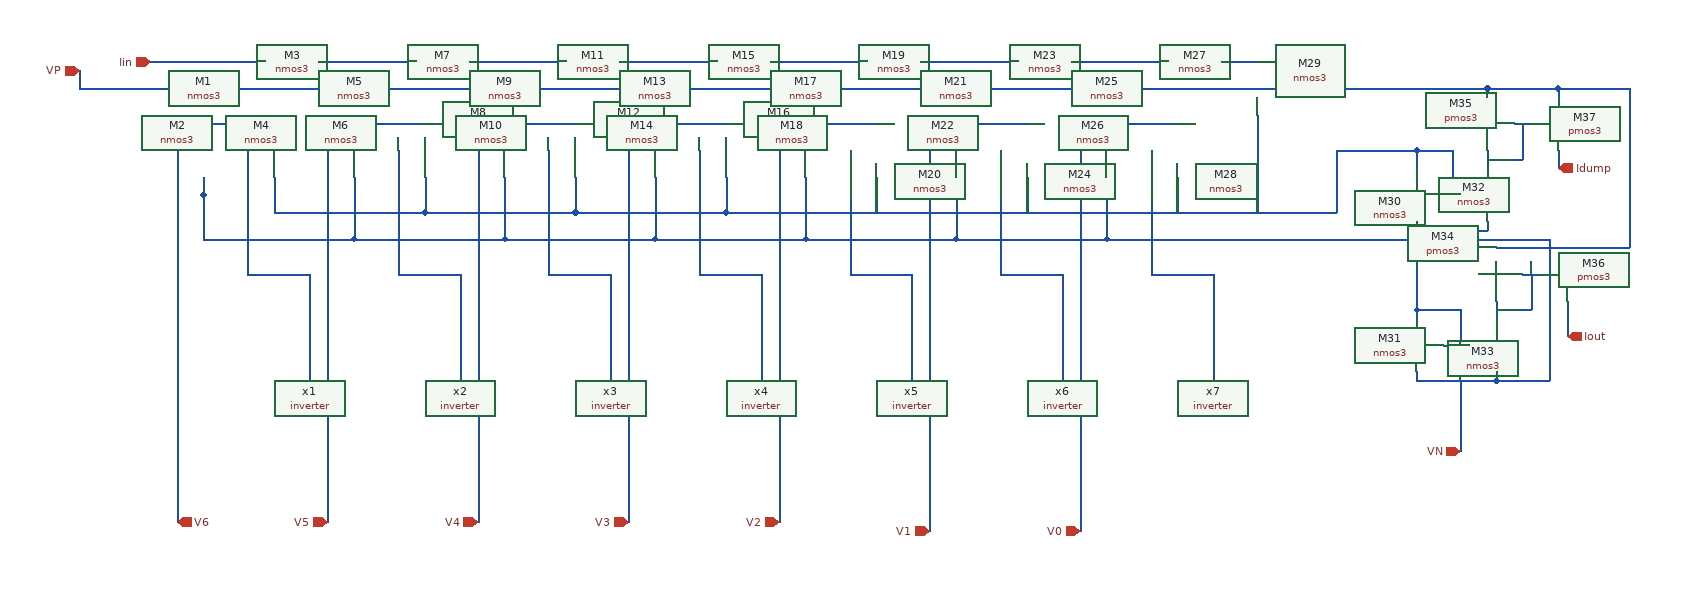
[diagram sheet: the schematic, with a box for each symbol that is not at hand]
v {xschem version=3.4.3 file_version=1.2
}
G {}
K {}
V {}
S {}
E {}
N 240 -30 310 -30 {
lab=VP}
N 240 30 240 40 {
lab=#net1}
N 240 100 240 120 {
lab=VP}
N 410 -30 480 -30 {
lab=VP}
N 410 30 410 40 {
lab=#net2}
N 370 -30 410 -30 {
lab=VP}
N 240 40 320 40 {
lab=#net1}
N 410 30 410 40 {
lab=#net2}
N 410 100 410 120 {
lab=VP}
N 490 100 490 120 {
lab=VP}
N 410 40 490 40 {
lab=#net2}
N 240 30 240 40 {
lab=#net1}
N 240 100 240 120 {
lab=VP}
N 320 100 320 120 {
lab=VP}
N 240 40 320 40 {
lab=#net1}
N 580 -30 650 -30 {
lab=VP}
N 580 30 580 40 {
lab=#net3}
N 540 -30 580 -30 {
lab=VP}
N 580 30 580 40 {
lab=#net3}
N 580 100 580 120 {
lab=VP}
N 660 100 660 120 {
lab=VP}
N 580 40 660 40 {
lab=#net3}
N 750 -30 820 -30 {
lab=VP}
N 750 30 750 40 {
lab=#net4}
N 710 -30 750 -30 {
lab=VP}
N 750 30 750 40 {
lab=#net4}
N 750 100 750 120 {
lab=VP}
N 830 100 830 120 {
lab=VP}
N 750 40 830 40 {
lab=#net4}
N 920 -30 990 -30 {
lab=VP}
N 920 30 920 40 {
lab=#net5}
N 880 -30 920 -30 {
lab=VP}
N 920 30 920 40 {
lab=#net5}
N 920 100 920 120 {
lab=VP}
N 1000 100 1000 120 {
lab=VP}
N 920 40 1000 40 {
lab=#net5}
N 1090 -30 1160 -30 {
lab=VP}
N 1090 30 1090 40 {
lab=#net6}
N 1050 -30 1090 -30 {
lab=VP}
N 1090 30 1090 40 {
lab=#net6}
N 1090 100 1090 120 {
lab=VP}
N 1170 100 1170 120 {
lab=VP}
N 1090 40 1170 40 {
lab=#net6}
N 1260 -30 1330 -30 {
lab=VP}
N 1260 30 1260 40 {
lab=#net7}
N 1220 -30 1260 -30 {
lab=VP}
N 1260 30 1260 40 {
lab=#net7}
N 1260 100 1260 120 {
lab=VP}
N 1340 100 1340 120 {
lab=VP}
N 1260 40 1340 40 {
lab=#net7}
N 1390 -30 1430 -30 {
lab=VP}
N 240 120 240 170 {
lab=VP}
N 240 170 410 170 {
lab=VP}
N 410 120 410 170 {
lab=VP}
N 410 170 580 170 {
lab=VP}
N 580 120 580 170 {
lab=VP}
N 750 120 750 170 {
lab=VP}
N 580 170 750 170 {
lab=VP}
N 920 120 920 170 {
lab=VP}
N 750 170 920 170 {
lab=VP}
N 1090 120 1090 170 {
lab=VP}
N 920 170 1090 170 {
lab=VP}
N 1260 120 1260 170 {
lab=VP}
N 1090 170 1260 170 {
lab=VP}
N 320 120 320 140 {
lab=VP}
N 320 140 490 140 {
lab=VP}
N 490 120 490 140 {
lab=VP}
N 490 140 660 140 {
lab=VP}
N 660 120 660 140 {
lab=VP}
N 660 140 830 140 {
lab=VP}
N 830 120 830 140 {
lab=VP}
N 1000 120 1000 140 {
lab=VP}
N 830 140 1450 140 {
lab=VP}
N 1170 120 1170 140 {
lab=VP}
N 1340 120 1340 140 {
lab=VP}
N 1430 30 1430 140 {
lab=VP}
N 180 -30 240 -30 {
lab=VP}
N 210 0 340 0 {
lab=VP}
N 340 0 380 0 {
lab=VP}
N 380 0 510 0 {
lab=VP}
N 510 0 550 -0 {
lab=VP}
N 550 -0 680 0 {
lab=VP}
N 680 0 720 0 {
lab=VP}
N 190 0 210 -0 {
lab=VP}
N 210 70 210 320 {
lab=V6}
N 380 70 380 320 {
lab=V5}
N 550 70 550 310 {
lab=V4}
N 550 310 550 320 {
lab=V4}
N 720 70 720 320 {
lab=V3}
N 890 70 890 320 {
lab=V2}
N 1060 70 1060 320 {
lab=V1}
N 1230 70 1230 320 {
lab=V0}
N 180 0 190 0 {
lab=VP}
N 720 -0 1400 0 {
lab=VP}
N 210 320 210 490 {
lab=V6}
N 380 320 380 490 {
lab=V5}
N 550 320 550 490 {
lab=V4}
N 720 320 720 490 {
lab=V3}
N 890 320 890 480 {
lab=V2}
N 1060 320 1060 480 {
lab=V1}
N 1230 320 1230 480 {
lab=V0}
N 1260 170 1450 170 {
lab=VP}
N 890 480 890 490 {
lab=V2}
N 1060 480 1060 500 {
lab=V1}
N 1230 480 1230 500 {
lab=V0}
N 290 70 290 210 {
lab=#net8}
N 290 210 360 210 {
lab=#net8}
N 360 210 360 330 {
lab=#net8}
N 460 70 460 200 {
lab=#net9}
N 460 200 460 210 {
lab=#net9}
N 460 210 530 210 {
lab=#net9}
N 530 210 530 330 {
lab=#net9}
N 630 70 630 210 {
lab=#net10}
N 630 210 700 210 {
lab=#net10}
N 700 210 700 330 {
lab=#net10}
N 800 70 800 210 {
lab=#net11}
N 800 210 870 210 {
lab=#net11}
N 870 210 870 330 {
lab=#net11}
N 970 70 970 210 {
lab=#net12}
N 970 210 1040 210 {
lab=#net12}
N 1040 210 1040 330 {
lab=#net12}
N 1140 70 1140 210 {
lab=#net13}
N 1140 210 1200 210 {
lab=#net13}
N 1200 210 1210 210 {
lab=#net13}
N 1210 210 1210 330 {
lab=#net13}
N 1310 70 1310 210 {
lab=#net14}
N 1310 210 1380 210 {
lab=#net14}
N 1380 210 1380 330 {
lab=#net14}
N 1450 140 1520 140 {
lab=VP}
N 1450 170 1510 170 {
lab=VP}
N 100 -20 100 0 {
lab=VP}
N 100 0 180 0 {
lab=VP}
N 1640 290 1670 290 {
lab=VP}
N 1640 120 1660 120 {
lab=VP}
N 1610 150 1610 160 {
lab=VN}
N 1610 160 1690 160 {
lab=VN}
N 1650 160 1650 170 {
lab=VN}
N 1610 320 1610 330 {
lab=VN}
N 1610 330 1700 330 {
lab=VN}
N 1700 320 1700 330 {
lab=VN}
N 1690 70 1690 90 {
lab=#net15}
N 1660 250 1660 290 {
lab=VP}
N 1610 70 1610 90 {
lab=VP}
N 1610 250 1610 260 {
lab=VP}
N 1770 70 1770 90 {
lab=Idump}
N 1720 40 1740 40 {
lab=#net15}
N 1730 40 1730 80 {
lab=#net15}
N 1610 70 1650 70 {
lab=VP}
N 1650 70 1650 120 {
lab=VP}
N 1690 80 1730 80 {
lab=#net15}
N 1610 250 1660 250 {
lab=VP}
N 1690 150 1690 160 {
lab=VN}
N 1700 240 1700 260 {
lab=#net16}
N 1780 240 1780 260 {
lab=Iout}
N 1730 210 1750 210 {
lab=#net16}
N 1740 210 1740 250 {
lab=#net16}
N 1700 250 1740 250 {
lab=#net16}
N 1510 170 1610 170 {
lab=VP}
N 1610 170 1610 250 {
lab=VP}
N 1520 70 1520 140 {
lab=VP}
N 1520 70 1610 70 {
lab=VP}
N 1400 0 1690 0 {
lab=VP}
N 1690 0 1690 10 {
lab=VP}
N 1690 -0 1770 0 {
lab=VP}
N 1770 0 1770 10 {
lab=VP}
N 1770 0 1850 0 {
lab=VP}
N 1850 0 1850 180 {
lab=VP}
N 1780 180 1850 180 {
lab=VP}
N 1700 180 1780 180 {
lab=VP}
N 1780 260 1780 280 {
lab=Iout}
N 1650 170 1760 170 {
lab=VN}
N 1760 170 1760 330 {
lab=VN}
N 1700 330 1760 330 {
lab=VN}
N 1660 330 1660 410 {
lab=VN}
C {madvlsi/nmos3.sym} 240 0 0 0 {name=M1
L=4
W=12
body=GND
nf=1
mult=1
ad="'int((nf+1)/2) * W/nf * 0.29'" 
pd="'2*int((nf+1)/2) * (W/nf + 0.29)'"
as="'int((nf+2)/2) * W/nf * 0.29'" 
ps="'2*int((nf+2)/2) * (W/nf + 0.29)'"
nrd="'0.29 / W'" nrs="'0.29 / W'"
sa=0 sb=0 sd=0
model=nfet_01v8
spiceprefix=X
}
C {madvlsi/nmos3.sym} 340 -30 3 0 {name=M3
L=4
W=12
body=GND
nf=1
mult=1
ad="'int((nf+1)/2) * W/nf * 0.29'" 
pd="'2*int((nf+1)/2) * (W/nf + 0.29)'"
as="'int((nf+2)/2) * W/nf * 0.29'" 
ps="'2*int((nf+2)/2) * (W/nf + 0.29)'"
nrd="'0.29 / W'" nrs="'0.29 / W'"
sa=0 sb=0 sd=0
model=nfet_01v8
spiceprefix=X
}
C {madvlsi/nmos3.sym} 410 0 0 0 {name=M5
L=4
W=12
body=GND
nf=1
mult=1
ad="'int((nf+1)/2) * W/nf * 0.29'" 
pd="'2*int((nf+1)/2) * (W/nf + 0.29)'"
as="'int((nf+2)/2) * W/nf * 0.29'" 
ps="'2*int((nf+2)/2) * (W/nf + 0.29)'"
nrd="'0.29 / W'" nrs="'0.29 / W'"
sa=0 sb=0 sd=0
model=nfet_01v8
spiceprefix=X
}
C {madvlsi/nmos3.sym} 510 -30 3 0 {name=M7
L=4
W=12
body=GND
nf=1
mult=1
ad="'int((nf+1)/2) * W/nf * 0.29'" 
pd="'2*int((nf+1)/2) * (W/nf + 0.29)'"
as="'int((nf+2)/2) * W/nf * 0.29'" 
ps="'2*int((nf+2)/2) * (W/nf + 0.29)'"
nrd="'0.29 / W'" nrs="'0.29 / W'"
sa=0 sb=0 sd=0
model=nfet_01v8
spiceprefix=X
}
C {madvlsi/nmos3.sym} 410 70 0 0 {name=M6
L=4
W=12
body=GND
nf=1
mult=1
ad="'int((nf+1)/2) * W/nf * 0.29'" 
pd="'2*int((nf+1)/2) * (W/nf + 0.29)'"
as="'int((nf+2)/2) * W/nf * 0.29'" 
ps="'2*int((nf+2)/2) * (W/nf + 0.29)'"
nrd="'0.29 / W'" nrs="'0.29 / W'"
sa=0 sb=0 sd=0
model=nfet_01v8
spiceprefix=X
}
C {madvlsi/nmos3.sym} 490 70 0 0 {name=M8
L=4
W=12
body=GND
nf=1
mult=1
ad="'int((nf+1)/2) * W/nf * 0.29'" 
pd="'2*int((nf+1)/2) * (W/nf + 0.29)'"
as="'int((nf+2)/2) * W/nf * 0.29'" 
ps="'2*int((nf+2)/2) * (W/nf + 0.29)'"
nrd="'0.29 / W'" nrs="'0.29 / W'"
sa=0 sb=0 sd=0
model=nfet_01v8
spiceprefix=X
}
C {madvlsi/nmos3.sym} 240 70 0 0 {name=M2
L=4
W=12
body=GND
nf=1
mult=1
ad="'int((nf+1)/2) * W/nf * 0.29'" 
pd="'2*int((nf+1)/2) * (W/nf + 0.29)'"
as="'int((nf+2)/2) * W/nf * 0.29'" 
ps="'2*int((nf+2)/2) * (W/nf + 0.29)'"
nrd="'0.29 / W'" nrs="'0.29 / W'"
sa=0 sb=0 sd=0
model=nfet_01v8
spiceprefix=X
}
C {madvlsi/nmos3.sym} 320 70 0 0 {name=M4
L=4
W=12
body=GND
nf=1
mult=1
ad="'int((nf+1)/2) * W/nf * 0.29'" 
pd="'2*int((nf+1)/2) * (W/nf + 0.29)'"
as="'int((nf+2)/2) * W/nf * 0.29'" 
ps="'2*int((nf+2)/2) * (W/nf + 0.29)'"
nrd="'0.29 / W'" nrs="'0.29 / W'"
sa=0 sb=0 sd=0
model=nfet_01v8
spiceprefix=X
}
C {madvlsi/nmos3.sym} 580 0 0 0 {name=M9
L=4
W=12
body=GND
nf=1
mult=1
ad="'int((nf+1)/2) * W/nf * 0.29'" 
pd="'2*int((nf+1)/2) * (W/nf + 0.29)'"
as="'int((nf+2)/2) * W/nf * 0.29'" 
ps="'2*int((nf+2)/2) * (W/nf + 0.29)'"
nrd="'0.29 / W'" nrs="'0.29 / W'"
sa=0 sb=0 sd=0
model=nfet_01v8
spiceprefix=X
}
C {madvlsi/nmos3.sym} 680 -30 3 0 {name=M11
L=4
W=12
body=GND
nf=1
mult=1
ad="'int((nf+1)/2) * W/nf * 0.29'" 
pd="'2*int((nf+1)/2) * (W/nf + 0.29)'"
as="'int((nf+2)/2) * W/nf * 0.29'" 
ps="'2*int((nf+2)/2) * (W/nf + 0.29)'"
nrd="'0.29 / W'" nrs="'0.29 / W'"
sa=0 sb=0 sd=0
model=nfet_01v8
spiceprefix=X
}
C {madvlsi/nmos3.sym} 580 70 0 0 {name=M10
L=4
W=12
body=GND
nf=1
mult=1
ad="'int((nf+1)/2) * W/nf * 0.29'" 
pd="'2*int((nf+1)/2) * (W/nf + 0.29)'"
as="'int((nf+2)/2) * W/nf * 0.29'" 
ps="'2*int((nf+2)/2) * (W/nf + 0.29)'"
nrd="'0.29 / W'" nrs="'0.29 / W'"
sa=0 sb=0 sd=0
model=nfet_01v8
spiceprefix=X
}
C {madvlsi/nmos3.sym} 660 70 0 0 {name=M12
L=4
W=12
body=GND
nf=1
mult=1
ad="'int((nf+1)/2) * W/nf * 0.29'" 
pd="'2*int((nf+1)/2) * (W/nf + 0.29)'"
as="'int((nf+2)/2) * W/nf * 0.29'" 
ps="'2*int((nf+2)/2) * (W/nf + 0.29)'"
nrd="'0.29 / W'" nrs="'0.29 / W'"
sa=0 sb=0 sd=0
model=nfet_01v8
spiceprefix=X
}
C {madvlsi/nmos3.sym} 750 0 0 0 {name=M13
L=4
W=12
body=GND
nf=1
mult=1
ad="'int((nf+1)/2) * W/nf * 0.29'" 
pd="'2*int((nf+1)/2) * (W/nf + 0.29)'"
as="'int((nf+2)/2) * W/nf * 0.29'" 
ps="'2*int((nf+2)/2) * (W/nf + 0.29)'"
nrd="'0.29 / W'" nrs="'0.29 / W'"
sa=0 sb=0 sd=0
model=nfet_01v8
spiceprefix=X
}
C {madvlsi/nmos3.sym} 850 -30 3 0 {name=M15
L=4
W=12
body=GND
nf=1
mult=1
ad="'int((nf+1)/2) * W/nf * 0.29'" 
pd="'2*int((nf+1)/2) * (W/nf + 0.29)'"
as="'int((nf+2)/2) * W/nf * 0.29'" 
ps="'2*int((nf+2)/2) * (W/nf + 0.29)'"
nrd="'0.29 / W'" nrs="'0.29 / W'"
sa=0 sb=0 sd=0
model=nfet_01v8
spiceprefix=X
}
C {madvlsi/nmos3.sym} 750 70 0 0 {name=M14
L=4
W=12
body=GND
nf=1
mult=1
ad="'int((nf+1)/2) * W/nf * 0.29'" 
pd="'2*int((nf+1)/2) * (W/nf + 0.29)'"
as="'int((nf+2)/2) * W/nf * 0.29'" 
ps="'2*int((nf+2)/2) * (W/nf + 0.29)'"
nrd="'0.29 / W'" nrs="'0.29 / W'"
sa=0 sb=0 sd=0
model=nfet_01v8
spiceprefix=X
}
C {madvlsi/nmos3.sym} 830 70 0 0 {name=M16
L=4
W=12
body=GND
nf=1
mult=1
ad="'int((nf+1)/2) * W/nf * 0.29'" 
pd="'2*int((nf+1)/2) * (W/nf + 0.29)'"
as="'int((nf+2)/2) * W/nf * 0.29'" 
ps="'2*int((nf+2)/2) * (W/nf + 0.29)'"
nrd="'0.29 / W'" nrs="'0.29 / W'"
sa=0 sb=0 sd=0
model=nfet_01v8
spiceprefix=X
}
C {madvlsi/nmos3.sym} 920 0 0 0 {name=M17
L=4
W=12
body=GND
nf=1
mult=1
ad="'int((nf+1)/2) * W/nf * 0.29'" 
pd="'2*int((nf+1)/2) * (W/nf + 0.29)'"
as="'int((nf+2)/2) * W/nf * 0.29'" 
ps="'2*int((nf+2)/2) * (W/nf + 0.29)'"
nrd="'0.29 / W'" nrs="'0.29 / W'"
sa=0 sb=0 sd=0
model=nfet_01v8
spiceprefix=X
}
C {madvlsi/nmos3.sym} 1020 -30 3 0 {name=M19
L=4
W=12
body=GND
nf=1
mult=1
ad="'int((nf+1)/2) * W/nf * 0.29'" 
pd="'2*int((nf+1)/2) * (W/nf + 0.29)'"
as="'int((nf+2)/2) * W/nf * 0.29'" 
ps="'2*int((nf+2)/2) * (W/nf + 0.29)'"
nrd="'0.29 / W'" nrs="'0.29 / W'"
sa=0 sb=0 sd=0
model=nfet_01v8
spiceprefix=X
}
C {madvlsi/nmos3.sym} 920 70 0 0 {name=M18
L=4
W=12
body=GND
nf=1
mult=1
ad="'int((nf+1)/2) * W/nf * 0.29'" 
pd="'2*int((nf+1)/2) * (W/nf + 0.29)'"
as="'int((nf+2)/2) * W/nf * 0.29'" 
ps="'2*int((nf+2)/2) * (W/nf + 0.29)'"
nrd="'0.29 / W'" nrs="'0.29 / W'"
sa=0 sb=0 sd=0
model=nfet_01v8
spiceprefix=X
}
C {madvlsi/nmos3.sym} 1000 70 0 0 {name=M20
L=4
W=12
body=GND
nf=1
mult=1
ad="'int((nf+1)/2) * W/nf * 0.29'" 
pd="'2*int((nf+1)/2) * (W/nf + 0.29)'"
as="'int((nf+2)/2) * W/nf * 0.29'" 
ps="'2*int((nf+2)/2) * (W/nf + 0.29)'"
nrd="'0.29 / W'" nrs="'0.29 / W'"
sa=0 sb=0 sd=0
model=nfet_01v8
spiceprefix=X
}
C {madvlsi/nmos3.sym} 1090 0 0 0 {name=M21
L=4
W=12
body=GND
nf=1
mult=1
ad="'int((nf+1)/2) * W/nf * 0.29'" 
pd="'2*int((nf+1)/2) * (W/nf + 0.29)'"
as="'int((nf+2)/2) * W/nf * 0.29'" 
ps="'2*int((nf+2)/2) * (W/nf + 0.29)'"
nrd="'0.29 / W'" nrs="'0.29 / W'"
sa=0 sb=0 sd=0
model=nfet_01v8
spiceprefix=X
}
C {madvlsi/nmos3.sym} 1190 -30 3 0 {name=M23
L=4
W=12
body=GND
nf=1
mult=1
ad="'int((nf+1)/2) * W/nf * 0.29'" 
pd="'2*int((nf+1)/2) * (W/nf + 0.29)'"
as="'int((nf+2)/2) * W/nf * 0.29'" 
ps="'2*int((nf+2)/2) * (W/nf + 0.29)'"
nrd="'0.29 / W'" nrs="'0.29 / W'"
sa=0 sb=0 sd=0
model=nfet_01v8
spiceprefix=X
}
C {madvlsi/nmos3.sym} 1090 70 0 0 {name=M22
L=4
W=12
body=GND
nf=1
mult=1
ad="'int((nf+1)/2) * W/nf * 0.29'" 
pd="'2*int((nf+1)/2) * (W/nf + 0.29)'"
as="'int((nf+2)/2) * W/nf * 0.29'" 
ps="'2*int((nf+2)/2) * (W/nf + 0.29)'"
nrd="'0.29 / W'" nrs="'0.29 / W'"
sa=0 sb=0 sd=0
model=nfet_01v8
spiceprefix=X
}
C {madvlsi/nmos3.sym} 1170 70 0 0 {name=M24
L=4
W=12
body=GND
nf=1
mult=1
ad="'int((nf+1)/2) * W/nf * 0.29'" 
pd="'2*int((nf+1)/2) * (W/nf + 0.29)'"
as="'int((nf+2)/2) * W/nf * 0.29'" 
ps="'2*int((nf+2)/2) * (W/nf + 0.29)'"
nrd="'0.29 / W'" nrs="'0.29 / W'"
sa=0 sb=0 sd=0
model=nfet_01v8
spiceprefix=X
}
C {madvlsi/nmos3.sym} 1260 0 0 0 {name=M25
L=4
W=12
body=GND
nf=1
mult=1
ad="'int((nf+1)/2) * W/nf * 0.29'" 
pd="'2*int((nf+1)/2) * (W/nf + 0.29)'"
as="'int((nf+2)/2) * W/nf * 0.29'" 
ps="'2*int((nf+2)/2) * (W/nf + 0.29)'"
nrd="'0.29 / W'" nrs="'0.29 / W'"
sa=0 sb=0 sd=0
model=nfet_01v8
spiceprefix=X
}
C {madvlsi/nmos3.sym} 1360 -30 3 0 {name=M27
L=4
W=12
body=GND
nf=1
mult=1
ad="'int((nf+1)/2) * W/nf * 0.29'" 
pd="'2*int((nf+1)/2) * (W/nf + 0.29)'"
as="'int((nf+2)/2) * W/nf * 0.29'" 
ps="'2*int((nf+2)/2) * (W/nf + 0.29)'"
nrd="'0.29 / W'" nrs="'0.29 / W'"
sa=0 sb=0 sd=0
model=nfet_01v8
spiceprefix=X
}
C {madvlsi/nmos3.sym} 1260 70 0 0 {name=M26
L=4
W=12
body=GND
nf=1
mult=1
ad="'int((nf+1)/2) * W/nf * 0.29'" 
pd="'2*int((nf+1)/2) * (W/nf + 0.29)'"
as="'int((nf+2)/2) * W/nf * 0.29'" 
ps="'2*int((nf+2)/2) * (W/nf + 0.29)'"
nrd="'0.29 / W'" nrs="'0.29 / W'"
sa=0 sb=0 sd=0
model=nfet_01v8
spiceprefix=X
}
C {madvlsi/nmos3.sym} 1340 70 0 0 {name=M28
L=4
W=12
body=GND
nf=1
mult=1
ad="'int((nf+1)/2) * W/nf * 0.29'" 
pd="'2*int((nf+1)/2) * (W/nf + 0.29)'"
as="'int((nf+2)/2) * W/nf * 0.29'" 
ps="'2*int((nf+2)/2) * (W/nf + 0.29)'"
nrd="'0.29 / W'" nrs="'0.29 / W'"
sa=0 sb=0 sd=0
model=nfet_01v8
spiceprefix=X
}
C {madvlsi/nmos3.sym} 1430 0 0 0 {name=M29
L=4
W=12
body=GND
nf=1
mult=1
ad="'int((nf+1)/2) * W/nf * 0.29'" 
pd="'2*int((nf+1)/2) * (W/nf + 0.29)'"
as="'int((nf+2)/2) * W/nf * 0.29'" 
ps="'2*int((nf+2)/2) * (W/nf + 0.29)'"
nrd="'0.29 / W'" nrs="'0.29 / W'"
sa=0 sb=0 sd=0
model=nfet_01v8
spiceprefix=X
}
C {devices/ipin.sym} 210 490 1 1 {name=p4 lab=V6}
C {devices/ipin.sym} 380 490 3 0 {name=p6 lab=V5}
C {devices/ipin.sym} 550 490 3 0 {name=p7 lab=V4}
C {devices/ipin.sym} 720 490 3 0 {name=p8 lab=V3}
C {devices/ipin.sym} 890 490 3 0 {name=p9 lab=V2}
C {devices/ipin.sym} 1060 500 3 0 {name=p10 lab=V1}
C {devices/ipin.sym} 1230 500 3 0 {name=p11 lab=V0}
C {./inverter.sym} 320 330 0 0 {name=x1}
C {./inverter.sym} 490 330 0 0 {name=x2}
C {./inverter.sym} 660 330 0 0 {name=x3}
C {./inverter.sym} 830 330 0 0 {name=x4}
C {./inverter.sym} 1000 330 0 0 {name=x5}
C {./inverter.sym} 1170 330 0 0 {name=x6}
C {./inverter.sym} 1340 330 0 0 {name=x7}
C {devices/iopin.sym} 100 -20 2 0 {name=p5 lab=VP}
C {devices/iopin.sym} 180 -30 2 0 {name=p3 lab=Iin}
C {madvlsi/nmos3.sym} 1610 120 2 0 {name=M30
L=4
W=12
body=GND
nf=1
mult=1
ad="'int((nf+1)/2) * W/nf * 0.29'" 
pd="'2*int((nf+1)/2) * (W/nf + 0.29)'"
as="'int((nf+2)/2) * W/nf * 0.29'" 
ps="'2*int((nf+2)/2) * (W/nf + 0.29)'"
nrd="'0.29 / W'" nrs="'0.29 / W'"
sa=0 sb=0 sd=0
model=nfet_01v8
spiceprefix=X
}
C {madvlsi/nmos3.sym} 1610 290 2 0 {name=M31
L=4
W=12
body=GND
nf=1
mult=1
ad="'int((nf+1)/2) * W/nf * 0.29'" 
pd="'2*int((nf+1)/2) * (W/nf + 0.29)'"
as="'int((nf+2)/2) * W/nf * 0.29'" 
ps="'2*int((nf+2)/2) * (W/nf + 0.29)'"
nrd="'0.29 / W'" nrs="'0.29 / W'"
sa=0 sb=0 sd=0
model=nfet_01v8
spiceprefix=X
}
C {madvlsi/nmos3.sym} 1690 120 0 0 {name=M32
L=4
W=12
body=GND
nf=1
mult=1
ad="'int((nf+1)/2) * W/nf * 0.29'" 
pd="'2*int((nf+1)/2) * (W/nf + 0.29)'"
as="'int((nf+2)/2) * W/nf * 0.29'" 
ps="'2*int((nf+2)/2) * (W/nf + 0.29)'"
nrd="'0.29 / W'" nrs="'0.29 / W'"
sa=0 sb=0 sd=0
model=nfet_01v8
spiceprefix=X
}
C {madvlsi/nmos3.sym} 1700 290 0 0 {name=M33
L=4
W=12
body=GND
nf=1
mult=1
ad="'int((nf+1)/2) * W/nf * 0.29'" 
pd="'2*int((nf+1)/2) * (W/nf + 0.29)'"
as="'int((nf+2)/2) * W/nf * 0.29'" 
ps="'2*int((nf+2)/2) * (W/nf + 0.29)'"
nrd="'0.29 / W'" nrs="'0.29 / W'"
sa=0 sb=0 sd=0
model=nfet_01v8
spiceprefix=X
}
C {madvlsi/pmos3.sym} 1690 40 0 1 {name=M35
L=4
W=12
body=VDD
nf=1
mult=1
ad="'int((nf+1)/2) * W/nf * 0.29'" 
pd="'2*int((nf+1)/2) * (W/nf + 0.29)'"
as="'int((nf+2)/2) * W/nf * 0.29'" 
ps="'2*int((nf+2)/2) * (W/nf + 0.29)'"
nrd="'0.29 / W'" nrs="'0.29 / W'"
sa=0 sb=0 sd=0
model=pfet_01v8
spiceprefix=X
}
C {madvlsi/pmos3.sym} 1770 40 0 0 {name=M37
L=4
W=12
body=VDD
nf=1
mult=1
ad="'int((nf+1)/2) * W/nf * 0.29'" 
pd="'2*int((nf+1)/2) * (W/nf + 0.29)'"
as="'int((nf+2)/2) * W/nf * 0.29'" 
ps="'2*int((nf+2)/2) * (W/nf + 0.29)'"
nrd="'0.29 / W'" nrs="'0.29 / W'"
sa=0 sb=0 sd=0
model=pfet_01v8
spiceprefix=X
}
C {madvlsi/pmos3.sym} 1700 210 0 1 {name=M34
L=4
W=12
body=VDD
nf=1
mult=1
ad="'int((nf+1)/2) * W/nf * 0.29'" 
pd="'2*int((nf+1)/2) * (W/nf + 0.29)'"
as="'int((nf+2)/2) * W/nf * 0.29'" 
ps="'2*int((nf+2)/2) * (W/nf + 0.29)'"
nrd="'0.29 / W'" nrs="'0.29 / W'"
sa=0 sb=0 sd=0
model=pfet_01v8
spiceprefix=X
}
C {madvlsi/pmos3.sym} 1780 210 0 0 {name=M36
L=4
W=12
body=VDD
nf=1
mult=1
ad="'int((nf+1)/2) * W/nf * 0.29'" 
pd="'2*int((nf+1)/2) * (W/nf + 0.29)'"
as="'int((nf+2)/2) * W/nf * 0.29'" 
ps="'2*int((nf+2)/2) * (W/nf + 0.29)'"
nrd="'0.29 / W'" nrs="'0.29 / W'"
sa=0 sb=0 sd=0
model=pfet_01v8
spiceprefix=X
}
C {devices/opin.sym} 1780 280 0 0 {name=p2 lab=Iout}
C {devices/opin.sym} 1770 90 0 0 {name=p12 lab=Idump}
C {devices/iopin.sym} 1660 410 0 0 {name=p1 lab=VN}
